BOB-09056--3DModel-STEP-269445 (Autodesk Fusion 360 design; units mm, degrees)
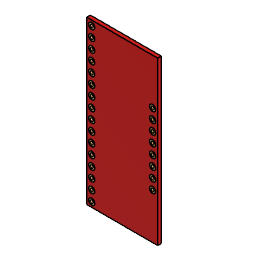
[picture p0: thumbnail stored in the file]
description: Part Number
part number: BOB-09056--3DModel-STEP-269445
base_feature "Base Feature"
